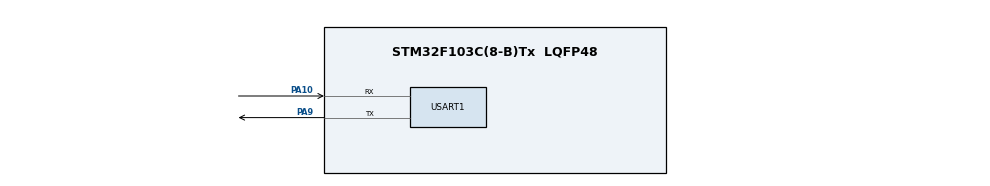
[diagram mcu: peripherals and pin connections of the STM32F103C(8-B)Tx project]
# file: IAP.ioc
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Mcu.Family=STM32F1
Mcu.Name=STM32F103C(8-B)Tx
Mcu.Package=LQFP48
NVIC.PriorityGroup=NVIC_PRIORITYGROUP_4
PA10.Mode=Asynchronous
PA10.Signal=USART1_RX
PA13.Mode=Serial_Wire
PA13.Signal=SYS_JTMS-SWDIO
PA14.Mode=Serial_Wire
PA14.Signal=SYS_JTCK-SWCLK
PA9.Mode=Asynchronous
PA9.Signal=USART1_TX
PD0-OSC_IN.Mode=HSE-External-Oscillator
PD0-OSC_IN.Signal=RCC_OSC_IN
PD1-OSC_OUT.Mode=HSE-External-Oscillator
PD1-OSC_OUT.Signal=RCC_OSC_OUT
ProjectManager.HeapSize=0x200
ProjectManager.StackSize=0x400
ProjectManager.TargetToolchain=MDK-ARM V5
RCC.AHBFreq_Value=72000000
RCC.APB1CLKDivider=RCC_HCLK_DIV2
RCC.APB1Freq_Value=36000000
RCC.APB1TimFreq_Value=72000000
RCC.APB2Freq_Value=72000000
RCC.APB2TimFreq_Value=72000000
RCC.HCLKFreq_Value=72000000
RCC.HSEDivPLL=RCC_HSE_PREDIV_DIV2
RCC.HSE_VALUE=16000000
RCC.PLLMUL=RCC_PLL_MUL9
RCC.PLLSourceVirtual=RCC_PLLSOURCE_HSE
RCC.SYSCLKFreq_VALUE=72000000
RCC.SYSCLKSource=RCC_SYSCLKSOURCE_PLLCLK
RCC.USBFreq_Value=72000000
USART1.VirtualMode=VM_ASYNC
board=custom

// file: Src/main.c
/* USER CODE BEGIN Header */
/**
  ******************************************************************************
  * @file           : main.c
  * @brief          : Main program body
  ******************************************************************************
  ** This notice applies to any and all portions of this file
  * that are not between comment pairs USER CODE BEGIN and
  * USER CODE END. Other portions of this file, whether
  * inserted by the user or by software development tools
  * are owned by their respective copyright owners.
  *
  * COPYRIGHT(c) 2018 STMicroelectronics
  *
  * Redistribution and use in source and binary forms, with or without modification,
  * are permitted provided that the following conditions are met:
  *   1. Redistributions of source code must retain the above copyright notice,
  *      this list of conditions and the following disclaimer.
  *   2. Redistributions in binary form must reproduce the above copyright notice,
  *      this list of conditions and the following disclaimer in the documentation
  *      and/or other materials provided with the distribution.
  *   3. Neither the name of STMicroelectronics nor the names of its contributors
  *      may be used to endorse or promote products derived from this software
  *      without specific prior written permission.
  *
  * THIS SOFTWARE IS PROVIDED BY THE COPYRIGHT HOLDERS AND CONTRIBUTORS "AS IS"
  * AND ANY EXPRESS OR IMPLIED WARRANTIES, INCLUDING, BUT NOT LIMITED TO, THE
  * IMPLIED WARRANTIES OF MERCHANTABILITY AND FITNESS FOR A PARTICULAR PURPOSE ARE
  * DISCLAIMED. IN NO EVENT SHALL THE COPYRIGHT HOLDER OR CONTRIBUTORS BE LIABLE
  * FOR ANY DIRECT, INDIRECT, INCIDENTAL, SPECIAL, EXEMPLARY, OR CONSEQUENTIAL
  * DAMAGES (INCLUDING, BUT NOT LIMITED TO, PROCUREMENT OF SUBSTITUTE GOODS OR
  * SERVICES; LOSS OF USE, DATA, OR PROFITS; OR BUSINESS INTERRUPTION) HOWEVER
  * CAUSED AND ON ANY THEORY OF LIABILITY, WHETHER IN CONTRACT, STRICT LIABILITY,
  * OR TORT (INCLUDING NEGLIGENCE OR OTHERWISE) ARISING IN ANY WAY OUT OF THE USE
  * OF THIS SOFTWARE, EVEN IF ADVISED OF THE POSSIBILITY OF SUCH DAMAGE.
  *
  ******************************************************************************
  */
/* USER CODE END Header */

#include "main.h"
#include "usart.h"
#include "gpio.h"

/* USER CODE BEGIN Includes */
#include "IAP.h"
/* USER CODE END Includes */

void SystemClock_Config(void);

int main(void)
{

  /* MCU Configuration--------------------------------------------------------*/

  /* Reset of all peripherals, Initializes the Flash interface and the Systick. */
  HAL_Init();

  /* Configure the system clock */
  SystemClock_Config();

  /* Initialize all configured peripherals */
  MX_GPIO_Init();
  MX_USART1_UART_Init();
  /* USER CODE BEGIN 2 */
  ucIAPInit();
  ucIAPProcess();
  /* USER CODE END 2 */

  /* Infinite loop */
  while (1)
  {

  }
}

void SystemClock_Config(void)
{
  RCC_OscInitTypeDef RCC_OscInitStruct = {0};
  RCC_ClkInitTypeDef RCC_ClkInitStruct = {0};

  /** Initializes the CPU, AHB and APB busses clocks
  */
  RCC_OscInitStruct.OscillatorType = RCC_OSCILLATORTYPE_HSE;
  RCC_OscInitStruct.HSEState = RCC_HSE_ON;
  RCC_OscInitStruct.HSEPredivValue = RCC_HSE_PREDIV_DIV1;
  RCC_OscInitStruct.HSIState = RCC_HSI_ON;
  RCC_OscInitStruct.PLL.PLLState = RCC_PLL_ON;
  RCC_OscInitStruct.PLL.PLLSource = RCC_PLLSOURCE_HSE;
  RCC_OscInitStruct.PLL.PLLMUL = RCC_PLL_MUL9;
  if (HAL_RCC_OscConfig(&RCC_OscInitStruct) != HAL_OK)
  {
    Error_Handler();
  }
  /** Initializes the CPU, AHB and APB busses clocks
  */
  RCC_ClkInitStruct.ClockType = RCC_CLOCKTYPE_HCLK|RCC_CLOCKTYPE_SYSCLK
                              |RCC_CLOCKTYPE_PCLK1|RCC_CLOCKTYPE_PCLK2;
  RCC_ClkInitStruct.SYSCLKSource = RCC_SYSCLKSOURCE_PLLCLK;
  RCC_ClkInitStruct.AHBCLKDivider = RCC_SYSCLK_DIV1;
  RCC_ClkInitStruct.APB1CLKDivider = RCC_HCLK_DIV2;
  RCC_ClkInitStruct.APB2CLKDivider = RCC_HCLK_DIV1;

  if (HAL_RCC_ClockConfig(&RCC_ClkInitStruct, FLASH_LATENCY_2) != HAL_OK)
  {
    Error_Handler();
  }
}

void Error_Handler(void)
{
}

/************************ (C) COPYRIGHT STMicroelectronics *****END OF FILE****/
